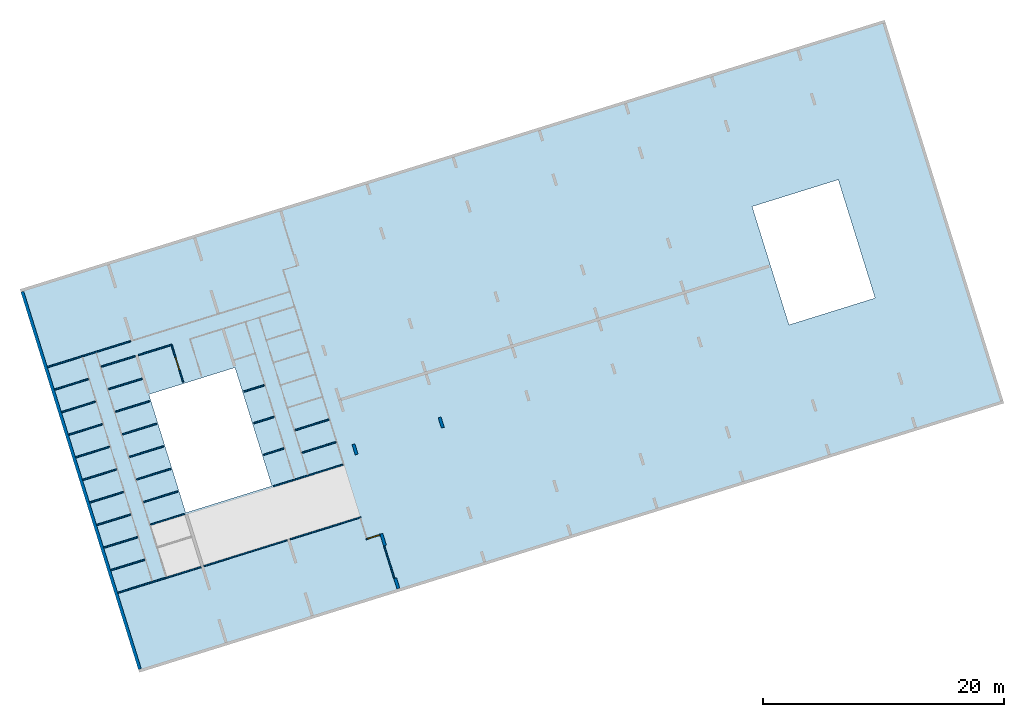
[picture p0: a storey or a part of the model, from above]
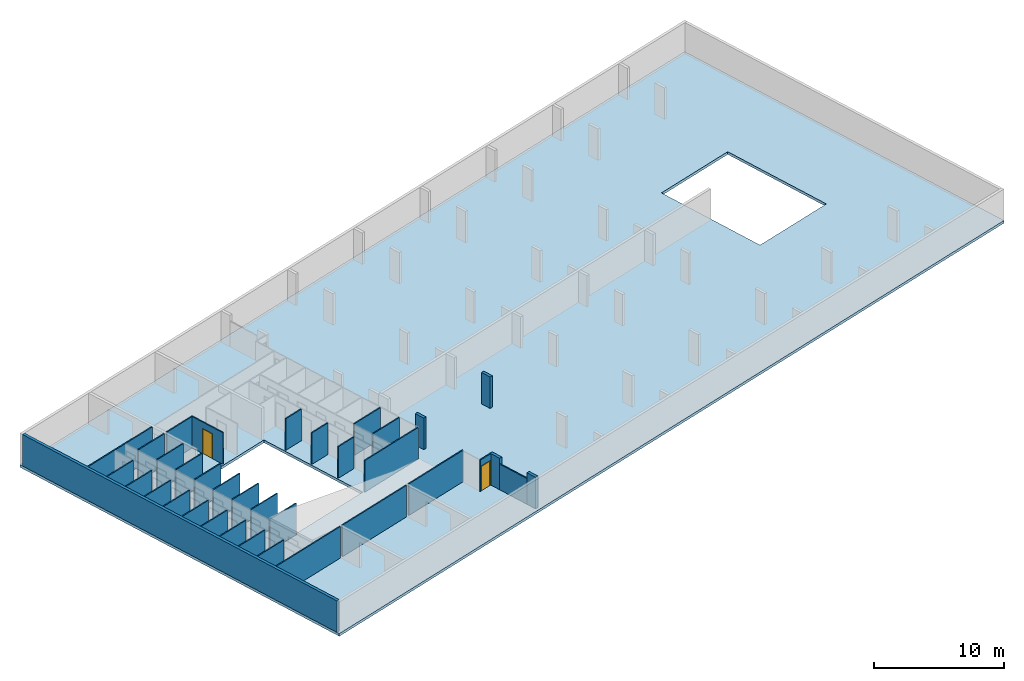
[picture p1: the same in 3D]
Properties of the parts of a building model (IFC4)

# File
Description: ViewDefinition [ReferenceView_V1.2], RevitIdentifiers [ContentGUID: 7b0fba1c-e461-43e6-a004-74300536da52, VersionGUID: db13fd34-4c88-41c4-b964-640beb15c8a9, NumberOfSaves: 300], Options [Excluded Entities: IfcGroup;], CoordinateReference [CoordinateBase: Survey Point, ProjectSite: Internal]
File name: MiniBIM 3.1 DO_00_VORM.ifc
Time: 2025-10-10T16:58:16+02:00
Organization: VORM Holding B.V.
Written by: IfcOpenShell 0.8.2
Made in: Bonsai 0.8.2

# IfcProject, 0000
LongName: Voorbeelmodel MiniBIM 3.1 DO-fase; Phase: PROJECTFASE

# IfcSite, Schiehaven
RefLatitude: 51, 54, 13, 78253; RefLongitude: 4, 27, 15, 99642; RefElevation: 3.5 m
Pset_SiteCommon - Reference: Project Information

# IfcBuilding, VORM huis
LongName: VORM huis
Pset_BuildingCommon - Reference: Project Information; NumberOfStoreys: 3; IsLandmarked: no
Pset_BuildingElementProxyCommon - Reference: Project Information; IsExternal: no
Pset_BuildingStoreyCommon - Reference: Project Information; AboveGround: no
Pset_BuildingSystemCommon - Reference: Project Information

# IfcBuildingStorey: Level:Level bouwniveau (PBP) (11)
In: VORM huis
Pset_BuildingStoreyCommon - Reference: Level bouwniveau (PBP)
Name | LongName | Elevation (m) | EntranceLevel | AboveGround
-1 kelder | -1 kelder | -3.2 | no | no
00 begane grond | begane grond | 0 | yes | yes
01 eerste verdieping | 01 eerste verdieping | 3.9 | no | yes
02 tweede verdieping | 02 tweede verdieping | 6.9 | no | yes
03 derde verdieping | 03 derde verdieping | 9.9 | no | yes
04 vierde verdieping | 04 vierde verdieping | 12.9 | no | yes
05 vijfde verdieping | 05 vijfde verdieping | 15.9 | no | yes
06 zesde verdieping | 06 zesde verdieping | 18.9 | no | yes
07 zevende verdieping | 07 zevende verdieping | 21.9 | no | yes
08 achtste verdieping | 08 achtste verdieping | 24.9 | no | yes
09 negende verdieping | 09 negende verdieping | 27.9 | no | yes

# IfcBuildingElementProxy: VORM_coordinatiepunt:CRS-coordinatiepunt, CRS-coordinatiepunt
In: 00 begane grond
Type - Classification: 00.00 (NL-SfB); Material: Blauw, Wit
Pset_BuildingElementProxyCommon - IsExternal: no; Reference: CRS-coordinatiepunt
Pset_EnvironmentalImpactIndicators - Reference: CRS-coordinatiepunt
Qto_BuildingElementProxyQuantities - NetSurfaceArea: 6.92096 m2; NetVolume: 0.458368 m3

# IfcBuildingElementProxy: VORM_coordinatiepunt:Lokaal-coordinatiepunt, Lokaal-coordinatiepunt
In: 00 begane grond
Type - Classification: 00.00 (NL-SfB); Material: Blauw, Wit
Pset_BuildingElementProxyCommon - IsExternal: no; Reference: Lokaal-coordinatiepunt
Pset_EnvironmentalImpactIndicators - Reference: Lokaal-coordinatiepunt
Qto_BuildingElementProxyQuantities - NetSurfaceArea: 7.78088 m2; NetVolume: 1.00022 m3

# IfcDoor: 32_DO_binnendeur enkel:binnendeur (31)
In: -1 kelder
Type - PredefinedType: DOOR; OperationType: REVOLVING; Classification: 32.30 binnenwandopeningen; gevuld met deuren, algemeen (verzamelniveau) (NL-SfB); Material: PD_a_binnenwandopeningen, metaal_aluminium_ntb
Type - Binnendeur:1 - PanelOperation: REVOLVING
Type - Pset_DoorCommon - IsExternal: no
OverallHeight: 2.35 m; OverallWidth: 1.05 m
Pset_DoorCommon - Reference: binnendeur
Pset_EnvironmentalImpactIndicators - Reference: binnendeur
Qto_DoorBaseQuantities - Width: 1.05 m; Height: 2.35 m; Perimeter: 2 m; Area: 2.4675 m2

# IfcDoor: 32_DO_binnendeur enkel:binnendeur zelfsluitend 30min (7)
In: -1 kelder
Type - PredefinedType: DOOR; Classification: 32.30 binnenwandopeningen; gevuld met deuren, algemeen (verzamelniveau) (NL-SfB); Material: PD_a_binnenwandopeningen, metaal_aluminium_ntb
Type - Pset_DoorCommon - IsExternal: no; FireRating: 30
OverallHeight: 2.35 m; OverallWidth: 1.05 m
Pset_DoorCommon - Reference: binnendeur zelfsluitend 30min
Pset_EnvironmentalImpactIndicators - Reference: binnendeur zelfsluitend 30min
Qto_DoorBaseQuantities - Width: 1.05 m; Height: 2.35 m; Perimeter: 2 m; Area: 2.4675 m2
Name
3 x Vluchtdeur | MiniBIM ILS - BouwwerkNummer: 01
4 x Vluchtdeur

# IfcOpeningElement (50)
In: -1 kelder
PredefinedType: OPENING
Name | Depth (m) | Height (m) | Width (m)
4 x Constructieve wand | 0.25 | 2.4 | 2.55 | Pset_EnvironmentalImpactIndicators - Reference: 28_WA_skelet_wand 250mm_gen; sets with these values: 2
2 x Funderingvloer |  | 7.5 | 10.3 | Pset_EnvironmentalImpactIndicators - Reference: 13_FL_funderingvloer 250mm; sets with these values: 2
2 x Vluchtdeur | 1.05 | 2.35 | 0.1 | Pset_EnvironmentalImpactIndicators - Reference: binnendeur zelfsluitend 30min; sets with these values: 2; Classification: 32.30 binnenwandopeningen; gevuld met deuren, algemeen (verzamelniveau) (NL-SfB)
Constructieve wand | 0.25 | 2.4 | 1.25 | Pset_EnvironmentalImpactIndicators - Reference: 28_WA_skelet_wand 250mm_gen; sets with these values: 2
Constructieve wand | 0.25 | 2.4 | 1.2 | Pset_EnvironmentalImpactIndicators - Reference: 28_WA_skelet_wand 250mm_gen; sets with these values: 2
4 x Vluchtdeur | 0.1 | 1.05 | 2.35
3 x Vluchtdeur | 0.1 | 2.35 | 1.05
2 x Vluchtdeur | 3.048 | 2.35 | 1.05
31 x Binnendeur | 0.1 | 1.05 | 2.35

# IfcRamp: 24_GM_TLB_hellingbaan:Stalling, Hellingbaan
In: -1 kelder
Classification: 24.20 trappen en hellingen; hellingen, algemeen (verzamelniveau) (NL-SfB); Material: beton_gewapend_ihw
Pset_EnvironmentalImpactIndicators - Reference: Stalling
Pset_RampCommon - IsExternal: no; Reference: Stalling
Pset_RampFlightCommon - Reference: Stalling; Slope: 12.1338 deg

# IfcSlab: Floor:13_FL_funderingvloer 250mm, Funderingvloer
In: -1 kelder
Type - PredefinedType: FLOOR; Material: beton_gewapend_ihw
Type - Pset_ReinforcementBarPitchOfSlab - Description: Funderingvloer
Type - Pset_SlabCommon - LoadBearing: yes
Classification: 13.20 vloeren op grondslag; constructief, algemeen (verzamelniveau) (NL-SfB)
Pset_EnvironmentalImpactIndicators - Reference: 13_FL_funderingvloer 250mm; sets with these values: 2
Pset_SlabCommon - IsExternal: no; LoadBearing: no; Reference: 13_FL_funderingvloer 250mm; PitchAngle: 0 deg
Qto_SlabBaseQuantities - Width: 33.35 m; Length: 75.25 m; Depth: 0.25 m; Perimeter: 946.194 m; GrossArea: 2509.59 m2; NetArea: 2355.09 m2; GrossVolume: 627.397 m3; NetVolume: 588.772 m3

# IfcSlab: Floor:28_FL_skelet_dakterrasvloer 250mm, Begaanbare dakvloer
In: 00 begane grond
Type - PredefinedType: ROOF; Material: beton_gewapend_ihw
Type - Pset_ReinforcementBarPitchOfSlab - Description: Begaanbare dakvloer
Type - Pset_SlabCommon - LoadBearing: yes
Classification: 27.10 daken; niet constructief, algemeen (verzamelniveau) (NL-SfB)
Pset_EnvironmentalImpactIndicators - Reference: 28_FL_skelet_dakterrasvloer 250mm; sets with these values: 2
Pset_SlabCommon - IsExternal: no; LoadBearing: no; PitchAngle: 0 deg; Reference: 28_FL_skelet_dakterrasvloer 250mm
Qto_SlabBaseQuantities - Width: 29.75 m; Length: 33.35 m; Depth: 0.25 m; Perimeter: 414.042 m; GrossArea: 992.163 m2; NetArea: 992.163 m2; GrossVolume: 248.041 m3; NetVolume: 248.041 m3

# IfcWall: Basic Wall:22_WA_afbouw_binnenwand 100mm_gen (49)
In: -1 kelder
Type - PredefinedType: STANDARD
Type - Pset_ReinforcementBarPitchOfWall - Description: Binnenwand
Type - Pset_WallCommon - LoadBearing: no
Classification: 22.10 binnenwanden; niet constructief, algemeen (verzamelniveau) (NL-SfB); Material: ntb_ntb_ntb
Qto_WallBaseQuantities - Width: 0.1 m
Pset_EnvironmentalImpactIndicators - Reference: 22_WA_afbouw_binnenwand 100mm_gen; sets with these values: 2
Pset_WallCommon - IsExternal: no; ExtendToStructure: no; Reference: 22_WA_afbouw_binnenwand 100mm_gen
Name | Height (m) | Length (m) | GrossFootprintArea (m2) | GrossVolume (m3) = NetVolume (m3) | GrossSideArea (m2) = NetSideArea (m2)
Binnenwand | 2.95 | 17.025 | 1.7025 | 4.77563 | 47.7563
Binnenwand | 2.95 | 6.05 | 0.605 | 1.78475 | 17.8475
Binnenwand | 2.95 | 6.15 | 0.615 | 1.81425 | 18.1425
5 x Binnenwand | 2.95 | 1.775 | 0.1775 | 0.523625 | 5.23625
3 x Binnenwand | 2.95 | 7.25 | 0.725 | 2.13875 | 21.3875
Binnenwand | 2.95 | 13.55 | 1.355 | 3.99725 | 39.9725
Binnenwand | 2.95 | 6.05 | 0.605 | 1.538 | 15.38
Binnenwand | 2.95 | 3.2 | 0.32 | 0.69725 | 6.9725
Binnenwand | 2.95 | 3.3 | 0.33 | 0.72675 | 7.2675
Binnenwand | 2.95 | 2.85 | 0.285 | 0.84075 | 8.4075
Binnenwand | 2.95 | 2.8 | 0.28 | 0.826 | 8.26
Binnenwand | 2.95 | 13.65 | 1.365 | 2.793 | 27.93
Binnenwand | 2.95 | 13.65 | 1.365 | 2.2995 | 22.995
23 x Binnenwand | 2.95 | 2.975 | 0.2975 | 0.877625 | 8.77625
2 x Binnenwand | 2.95 | 19.55 | 1.955 | 3.29975 | 32.9975
Binnenwand | 2.95 | 2.975 | 0.2975 | 0.827224 | 8.27224
Binnenwand | 2.95 | 1.1 | 0.11 | 0.07775 | 0.7775
2 x Binnenwand | 2.4 | 2.85 | 0.285 | 0.684 | 6.84
Binnenwand | 2.95 | 1.2 | 0.12 | 0.10725 | 1.0725

# IfcWall: Basic Wall:28_WA_skelet_keerwand 250mm_gen (4)
In: -1 kelder
Type - PredefinedType: STANDARD
Type - Pset_ReinforcementBarPitchOfWall - Description: Constructieve keerwand
Type - Pset_WallCommon - LoadBearing: yes
Classification: 28.20 hoofddraagconstructies; wanden en vloeren, algemeen (verzamelniveau) (NL-SfB); Material: beton_gewapend_ihw
Qto_WallBaseQuantities - Height: 2.95 m; Width: 0.25 m
Pset_EnvironmentalImpactIndicators - Reference: 28_WA_skelet_keerwand 250mm_gen; sets with these values: 2
Pset_WallCommon - IsExternal: no; Reference: 28_WA_skelet_keerwand 250mm_gen; LoadBearing: no; ExtendToStructure: no
Name | Length (m) | GrossFootprintArea (m2) | GrossVolume (m3) = NetVolume (m3) | GrossSideArea (m2) = NetSideArea (m2)
2 x Constructieve keerwand | 32.85 | 8.2125 | 24.2269 | 96.9075
2 x Constructieve keerwand | 75.25 | 18.8125 | 55.4969 | 221.988

# IfcWall: Basic Wall:28_WA_skelet_wand 250mm_gen (54)
In: -1 kelder
Type - PredefinedType: STANDARD
Type - Pset_ReinforcementBarPitchOfWall - Description: Constructieve wand
Type - Pset_WallCommon - LoadBearing: yes
Classification: 28.20 hoofddraagconstructies; wanden en vloeren, algemeen (verzamelniveau) (NL-SfB); Material: beton_gewapend_ihw
Qto_WallBaseQuantities - Width: 0.25 m
Pset_EnvironmentalImpactIndicators - Reference: 28_WA_skelet_wand 250mm_gen; sets with these values: 2
Pset_WallCommon - IsExternal: no; LoadBearing: no; Reference: 28_WA_skelet_wand 250mm_gen
Name | Height (m) | Length (m) | GrossFootprintArea (m2) | GrossVolume (m3) | GrossSideArea (m2) = NetSideArea (m2) | NetVolume (m3) | ExtendToStructure
Constructieve wand | 2.95 | 37.25 | 9.3125 | 27.4719 | 109.888 | 27.4719 | no
Constructieve wand | 2.95 | 6.65 | 1.6625 | 3.37438 | 13.4975 | 3.37438 | no
32 x Constructieve wand | 2.95 | 0.9 | 0.225 | 0.66375 | 2.655 | 0.66375 | no
4 x Constructieve wand | 2.95 | 1.025 | 0.25625 | 0.755937 | 3.02375 | 0.755937 | no
10 x Constructieve wand | 2.95 | 1.025 | 0.25625 | 0.755937 | 3.02375 | 0.755938 | no
2 x Constructieve wand | 2.95 | 1.025 | 0.25625 | 0.755938 | 3.02375 | 0.755938 | no
Constructieve wand | 2.95 | 6.65 | 1.6625 | 3.37437 | 13.4975 | 3.37437 | no
Constructieve wand | 2.95 | 11.15 | 2.7875 | 5.89937 | 23.5975 | 5.89937 | no
Constructieve wand | 2.48446 | 4.5 | 1.125 | 2.79502 | 11.1801 | 2.76479 | yes
Constructieve wand | 2.95 | 11.15 | 2.7875 | 5.97312 | 23.8925 | 5.97312 | no

# IfcSpaceType, no part of this type: 71_PA_Parkeerplaats auto:openbaar 90° - 2400
PredefinedType: USERDEFINED; Classification: 71.10 vaste verkeersvoorzieningen; standaard, algemeen (verzamelniveau) (NL-SfB); Material: markering

# IfcSpaceType, no part of this type: 71_PA_Parkeerplaats auto:stalling 90° - 2400
Classification: 71.10 vaste verkeersvoorzieningen; standaard, algemeen (verzamelniveau) (NL-SfB); Material: markering

# IfcSpaceType, no part of this type: 71_PA_Parkeerplaats bakfiets:Parkeerplaats bakfiets
PredefinedType: USERDEFINED; Classification: 71.10 vaste verkeersvoorzieningen; standaard, algemeen (verzamelniveau) (NL-SfB); Material: parkeervak

# IfcSpaceType, no part of this type: 71_PA_Parkeerplaats fiets:Parkeerplaats fiets hoog
PredefinedType: USERDEFINED; Classification: 71.10 vaste verkeersvoorzieningen; standaard, algemeen (verzamelniveau) (NL-SfB); Material: markering

# IfcSpaceType, no part of this type: 71_PA_Parkeerplaats fiets:Parkeerplaats fiets laag
PredefinedType: USERDEFINED; Classification: 71.10 vaste verkeersvoorzieningen; standaard, algemeen (verzamelniveau) (NL-SfB); Material: markering

# IfcSpaceType, no part of this type: 71_PA_Parkeerplaats scooter:Parkeerplaats scooter
PredefinedType: USERDEFINED; Classification: 71.10 vaste verkeersvoorzieningen; standaard, algemeen (verzamelniveau) (NL-SfB); Material: parkeervak
